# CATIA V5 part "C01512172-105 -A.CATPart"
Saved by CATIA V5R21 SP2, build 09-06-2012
Part number: C01512172-105
Revision: ---
Description: PROPRIETARY NOTICE (do not delete / modify)  ***************************************************************************************************  LA SOCIETE EN COMMANDITE  AIRBUS CANADA  ("AIRBUS CANADA")  PAR  L'INTERMEDIAIRE  DE  SES  DIVISIONS  ET/OU  FILIALES  CORPORATIVES,  FOURNIT  LES PRESENTES  INFORMATIONS  AU  GOUVERNEMENT  A  TITRE CONFIDENTIEL. CES  INFORMATIONS ONT UNE TENEUR CONFIDENTIELLE,  AVEC DROITS DE PROPRIETE,  ET NOUS LES CONSIDERONS  EXCLUS  DE   L'APPLICATION  DE  LA LOI SUR L'ACCES A L'INFORMATION  (CANADA),  LES  LOIS  SUR  L'ACCES  A  L'INFORMATION  EUROPEENNES,  LE FREEDOM OF INFORMATION ACT (ETATS-UNIS) ET D'AUTRES LOIS SEMBLABLES. ELLES  PEUVENT  AUSSI  CONSTITUER DES SECRETS INDUSTRIELS DE NOTRE SOCIETE OU DE TIERCES PARTIES. LA DIVULGATION  PUBLIQUE  DE CES  INFORMATIONS NUIRAIT A AIRBUS CANADA OU A DES TIERCES PARTIES.  CES INFORMATIONS PEUVENT EGALEMENT CONTENIR  DES DONNEES QUI SONT CONTROLEE PAR DES LOIS DE CONTROLE DES EXPORTATIONS DU CANADA, L’EUROPE OU LES  ETATS-  UNIS. TOUTE EXPORTATION OU REEXPORTATION DE DONNEES CONTROLEES SANS AUTORISATION EST STRICTEMENT INTERDITE.  TOUTE INTENTION DE LES DIVULGUER EN TOUT OU EN PARTIE DEVRA ETRE SIGNIFIEE A L'AVANCE ET PAR ECRIT AU VICE-  PRESIDENT, SERVICES JURIDIQUES ET CONFORMITE ET SECRETAIRE CORPORATIF D'AIRBUS CANADA.    AIRBUS CANADA LIMITED PARTNERSHIP  ("AIRBUS CANADA"),  BY ITS AFFILIATES AND/OR SUBSIDIARIES, PROVIDES THIS  INFORMATION TO THE GOVERNMENT IN CONFIDENCE. THIS IS PROPRIETARY CONFIDENTIAL INFORMATION WHICH WE CONSIDER  EXCLUDED  FROM  THE  APPLICATION OF THE ACCESS TO INFORMATION ACT (CANADA),  THE FREEDOM OF INFORMATION ACT  (U.S.A.),  THE ACCESS TO INFORMATION LAWS IN EUROPE, AND OTHER SIMILAR LEGISLATION. AND MAY ALSO CONSTITUTE  TRADE SECRETS OF OUR  COMPANY OR THIRD PARTIES.  PUBLIC  RELEASE  OF  THIS INFORMATION  WOULD BE HARMFUL TO  AIRBUS CANADA OR THIRD PARTIES.  THIS  INFORMATION  MAY  ALSO  CONTAIN DATA THAT IS CONTROLLED BY CANADIAN,  EUROPEAN, OR U.S.A. EXPORT CONTROL LAWS. ANY UNAUTHORIZED EXPORT OR RE-EXPORT OF ANY EXPORT CONTROLLED DATA  IS STRICTLY PROHIBITED  ANY INTENTION TO DISCLOSE SUCH INFORMATION,  OR  PART THEREOF,  MUST BE NOTIFIED IN  ADVANCE AND IN WRITING TO THE VICE PRESIDENT, LEGAL AND COMPLIANCE AND CORPORATE SECRETARY OF AIRBUS CANADA.        LES RENSEIGNEMENTS,  LES DONNEES  ET  DESSINS  TECHNIQUES  DIVULGUES  DANS  LES PRESENTES SONT LA PROPRIETE  EXCLUSIVE DE LA SOCIETE EN COMMANDITE AIRBUS CANADA ("AIRBUS CANADA") OU COMPORTENT DES DROITS DE PROPRIETE  APPARTENANT  A  AUTRUI ET NE PEUVENT ETRE DIVULGUES  A  QUICONQUE  NI  UTILISES PAR QUI QUE CE SOIT SANS LE  CONSENTEMENT  ECRIT  D’AIRBUS  CANADA.  LE DETENTEUR DES  PRESENTES  S'ENGAGE, DANS TOUTES CIRCONSTANCES, A  GARDER CONFIDENTIELS LES DONNEES ET DESSINS TECHNIQUES QU'ELLES CONTIENNENT.   CE QUI PRECEDE NE S'APPLIQUE  PAS  AUX PERSONNES  QUI  ONT DES DROITS DE PROPRIETE SUR CES RENSEIGNEMENTS,  DONNEES TECHNIQUES ET DESSINS  DANS LA MESURE OU CES DROITS EXISTENT.    THE INFORMATION,  TECHNICAL DATA  AND  DESIGNS DISCLOSED HEREIN ARE THE EXCLUSIVE PROPERTY OF AIRBUS CANADA  LIMITED PARTNERSHIP  ("AIRBUS CANADA")  OR  CONTAIN PROPRIETARY RIGHTS OF OTHERS  AND ARE NOT TO BE USED OR  DISCLOSED  TO  OTHERS WITHOUT THE WRITTEN CONSENT OF AIRBUS CANADA.  THE RECIPIENT OF THIS DOCUMENT, BY ITS  RETENTION  AND  USE  AGREES TO  HOLD  IN  CONFIDENCE  THE  TECHNICAL DATA AND DESIGNS CONTAINED HEREIN. THE  FOREGOING SHALL NOT APPLY TO PERSONS HAVING PROPRIETARY RIGHTS TO SUCH INFORMATION,  TECHNICAL DATA OR SUCH  DESIGNS TO THE EXTENT THAT SUCH RIGHTS EXIST.    Copyright 2020 Airbus Canada Limited Partnership. All Rights Reserved.  ***********************************
Property "Title": "AXIS, EXT HDL, FWD PASS DR"
Property "Dataset Type": "DETAIL"
Property "Supplier Name And CAGE Code": "AIRBUS CANADA LIMITED PARTNERSHIP L0J48"
Property "Major Supplier Code": "LP"
Property "3D Only": "Y"
Property "Material Form": "BAR - ROUND"
Property "Finish Code": "T002"
Property "PCCN": "2"
Property "Organization": "DESIGN"
Property "Design Authority Program": "BD-500"
Property "Color Coded": "N/A"
Property "Thickness": 0
Property "Inside Diameter": 0
Property "Outside Diameter": 1.25
Property "Length": 0
Property "Width": 0
Property "Wall": 0
Property "Wire Gauge": "-"
Property "Alloy": "6AL-4V"
Property "Final Condition": "ANL"
Property "Density": "N/A"
Property "Form": "N/A"
Property "Grade/Composition": "N/A"
Property "Material Class": "N/A"
Property "Mesh Cell Size": "N/A"
Property "Standard Spec Die": "N/A"
Property "Type": "N/A"
Property "Style": "N/A"
Property "MFG Process": "MACHINED"
Property "Material Specification Production": "AMS4928"
Property "Material Description Production": "TITANIUM"
Property "Dimensions": "DIMENSIONS ARE IN INCHES"
Property "Roughness": "ALL MACHINED SURFACES 125 Ra MAX"
Property "Eng. Tolerances": "LINEAR .XX= +/-.03; .XXX= +/-.010; ANGULAR= +/-0.5 DEG"
Property "Tool Design Tolerances": "LINEAR .X= +/-.06; .XX= +/-.015; .XXX= +/-.005; .XXXX= +/-.001; ANGULAR= +/-0.5 DEG"
Property "Project": "BA"
Publications: "PartBody", "DATUM_A", "DATUM_B"
Material "TI-6AL-4V": density 4428.78 kg/m3, Young's modulus 1.11695e+11 Pa, Poisson ratio 0.31
Bounding box of the stored display mesh (mm): x -46.097 to 27.171, y -10.789 to 10.789, z -13.834 to 14.462
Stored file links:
  C:\Users\CQQZ006\Desktop\A220钢钛件\舱门\C01512172-105\C01512172-105 -A.CATPart

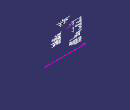
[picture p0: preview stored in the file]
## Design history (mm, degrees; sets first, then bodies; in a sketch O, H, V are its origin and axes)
Parameters
  deleted_LENGTH = 12.7 mm
AxisSystem1 "Absolute Axis System": origin (0, 0, 0), X (1, 0, 0), Y (0, 1, 0), Z (0, 0, 1)
Part_3D_Annotations1 "CATTPSSet"
Set1 "Pilot_Holes"
  Set2 "3/16"
    Set3 "Copied From C01512283-001"
      Line1 "Fix Orientation 1": stored without definition
      Point1 "Fix Point 1": stored without definition
    Set4 "Copied From C01512284-001"
      Line2 "Fix Orientation 1": stored without definition
      Point2 "Fix Point 1": stored without definition
Set5 "References"
  Plane1 "REFERENCE PLANE": type Offset, RefPlane face of Shaft1 from Sketch1.L7, Offset 0, reversed
  Line3 "REFERENCE AXIS": type PtPt, FirstPoint Point3, SecondPoint Point4
Set6 "Geometrical Set for 3D Annotations"
  Set7 "No Show Geometry"
    MultiExtract1 "DATUM_A": ListOfMultiExtractConstraints (MultiExtractConstraint face of Shaft1 from Sketch1.L1; MultiExtractConstraint face of Shaft1 from Sketch1.L8)
    Extract1 "DATUM_B": ExtractElem face of Shaft1 from Sketch1.L7
    Plane2: linked copy from another document
  Set8 "Surfaces for 3D Annotations"
    Set9 "VIEW_CHANGES_GS"
      MultiExtract2 "Changes from -001": ListOfMultiExtractConstraints (MultiExtractConstraint face of Shaft1 from Sketch1.L8; MultiExtractConstraint face of Shaft1 from Sketch1.L1)
Set10 "Construction_Geometry"
  Point3: type Center, Curve edge [face of Shaft1 from Sketch1.L4 | face of Shaft1 from Sketch1.L1]
  Point4: type Center, Curve edge [face of Shaft1 from Sketch1.L8 | face of Shaft1 from Sketch1.L2]
Body1 "PartBody" (main body)
  Sketch1 on zx-plane, origin (0, 0, 0), H (-1, 0, 0), V (0, 0, 1)
    point P1 (-27.1709, 6.3386)
    line L1 (-27.1709, 6.3386) -> (-1.905, 6.3386)
    line L2 (46.0972, 6.3386) -> (46.0972, 4.3663)
    line L3 (46.0972, 4.3663) -> (-23.126, 4.3663)
    line L4 (-27.1709, 0) -> (-27.1709, 6.3386)
    point P2 (46.0972, 6.3386)
    line L5 (-1.524, 6.7196) -> (-1.524, 10.795)
    line L6 (-1.524, 10.795) -> (0, 10.795)
    line L7 (0, 10.795) -> (0, 6.7196)
    line L8 (0.381, 6.3386) -> (46.0972, 6.3386)
    arc A1 centre (0.381, 6.7196) radius 0.381 from (0, 6.7196) to (0.381, 6.3386) ccw
    arc A2 centre (-1.905, 6.7196) radius 0.381 from (-1.524, 6.7196) to (-1.905, 6.3386) cw
    construction line L9 (5.0246, -6.3386) -> (20.4672, -6.3386)
    point P11 (5.0246, -6.3386)
    point P12 (20.4672, -6.3386)
    point P13 (-27.1709, 0)
    line L10 (-27.1709, 0) -> (-25.6469, 0)
    line L11 (-25.6469, 0) -> (-23.126, 4.3663)
    distance P1 P2 = 73.2681 (reference)
    distance L6 H = 10.795
    length L6 = 1.524
    distance L4 V = 27.1709
    distance H L3 = 4.3663
    distance L3 L8 = 1.9723 (reference)
    radius A1 = 0.381
    radius A2 = 0.381
    distance V L2 = 46.0972
    distance L3 L8 = 1.9723 (reference)
    distance L9 L8 = 12.6771
    length L10 = 1.524
    angle L11 L10 = 60
    distance P12 L2 = 25.6299
    distance P11 L4 = 32.1955
    horizontal: L1 H, L3 H, L6 H, L9 H, L10 H
    vertical: L2 V, L4 V, L5 V, L7 V
    coincidence: L1 L8, L7 V, P13 L4, P13 H, P13 L10
    tangency: A1 L7, A1 L8, A2 L5, A2 L1
    symmetry: L8 L9 H
  Shaft1: profile Sketch1, axis Sketch1.H, angle 360
  Chamfer1: length 1.016, angle 45, on edge [face of Shaft1 from Sketch1.L8 | face of Shaft1 from Sketch1.L2]; edge [face of Shaft1 from Sketch1.L4 | face of Shaft1 from Sketch1.L1]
